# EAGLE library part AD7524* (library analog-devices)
8-Bit Buffered Multiplying DAC Source: http://www.analog.com/UploadedFiles/Data_Sheets/888358036ad7524.pdf

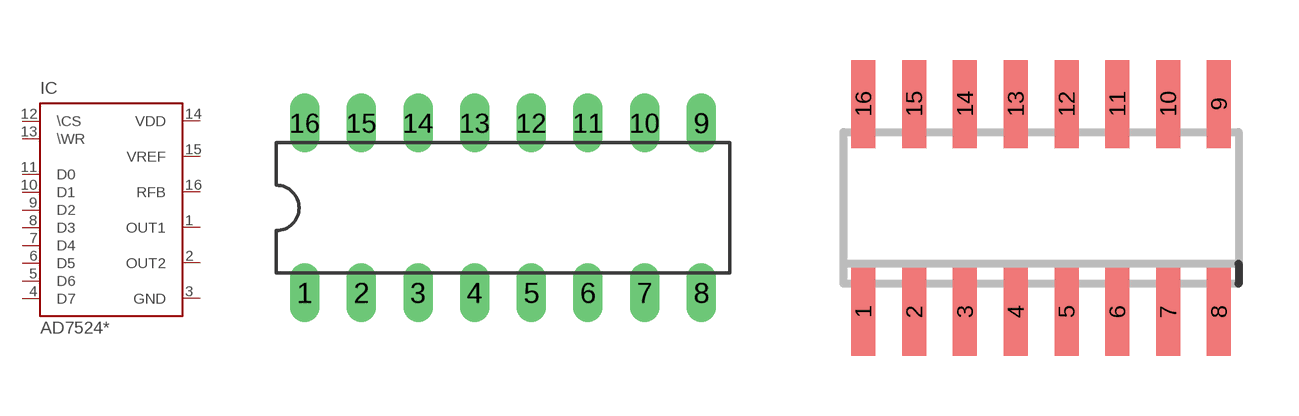
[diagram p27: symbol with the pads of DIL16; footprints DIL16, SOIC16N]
Designator prefix IC

## AD7524JN, AD7524KN, AD7524LN  [DIL16]
1  OUT1  pas
2  OUT2  pas
3  GND  pwr
4  D7  in
5  D6  in
6  D5  in
7  D4  in
8  D3  in
9  D2  in
10  D1  in
11  D0  in
12  \CS  in
13  \WR  in
14  VDD  pwr
15  VREF  in
16  RFB  pas

## AD7524JR  [SOIC16N]
Pads as for DIL16

## AD7524JP, AD7524KP, AD7524LP  [PLCC20]
2  OUT1  pas
3  OUT2  pas
4  GND  pwr
5  D7  in
7  D6  in
8  D5  in
9  D4  in
10  D3  in
12  D2  in
13  D1  in
14  D0  in
15  \CS  in
17  \WR  in
18  VDD  pwr
19  VREF  in
20  RFB  pas

## AD7524SE, AD7524TE, AD7524UE  [LCC20]
Pads as for PLCC20

## AD7524AQ, AD7524BQ, AD7524CQ, AD7524SQ, AD7524TQ, AD7524UQ  [DIL16]
Pads as for DIL16

## Footprint DIL16 (pad centres in mm)
Dual In Line Package
drill 0.813 long: 1 -8.89,-3.81; 2 -6.35,-3.81; 3 -3.81,-3.81; 4 -1.27,-3.81; 5 1.27,-3.81; 6 3.81,-3.81; 7 6.35,-3.81; 8 8.89,-3.81; 9 8.89,3.81; 10 6.35,3.81; 11 3.81,3.81; 12 1.27,3.81; 13 -1.27,3.81; 14 -3.81,3.81; 15 -6.35,3.81; 16 -8.89,3.81

## Footprint SOIC16N (pad centres in mm)
SMALL OUTLINE INTEGRATED CIRCUIT
smd 0.6 x 2.2: 1 -4.445,-2.6; 2 -3.175,-2.6; 3 -1.905,-2.6; 4 -0.635,-2.6; 5 0.635,-2.6; 6 1.905,-2.6; 7 3.175,-2.6; 8 4.445,-2.6; 9 4.445,2.6; 10 3.175,2.6; 11 1.905,2.6; 12 0.635,2.6; 13 -0.635,2.6; 14 -1.905,2.6; 15 -3.175,2.6; 16 -4.445,2.6

## Footprint PLCC20 (pad centres in mm)
Plastic Leaded Chip Carrier IPC standard
smd 0.6 x 2.2: 1 0,4.3; 2 -1.27,4.3; 3 -2.54,4.3; 9 -2.54,-4.3; 10 -1.27,-4.3; 11 0,-4.3; 12 1.27,-4.3; 13 2.54,-4.3; 19 2.54,4.3; 20 1.27,4.3
smd 2.2 x 0.6: 4 -4.3,2.54; 5 -4.3,1.27; 6 -4.3,0; 7 -4.3,-1.27; 8 -4.3,-2.54; 14 4.3,-2.54; 15 4.3,-1.27; 16 4.3,0; 17 4.3,1.27; 18 4.3,2.54

## Footprint LCC20 (pad centres in mm)
PLASTIC LEADED CHIP CARRIER
smd 0.8 x 3.4: 1 0,3.8
smd 0.8 x 2: 2 -1.27,4.5; 3 -2.54,4.5; 9 -2.54,-4.5; 10 -1.27,-4.5; 11 0,-4.5; 12 1.27,-4.5; 13 2.54,-4.5; 19 2.54,4.5; 20 1.27,4.5
smd 2 x 0.8: 4 -4.5,2.54; 5 -4.5,1.27; 6 -4.5,0; 7 -4.5,-1.27; 8 -4.5,-2.54; 14 4.5,-2.54; 15 4.5,-1.27; 16 4.5,0; 17 4.5,1.27; 18 4.5,2.54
